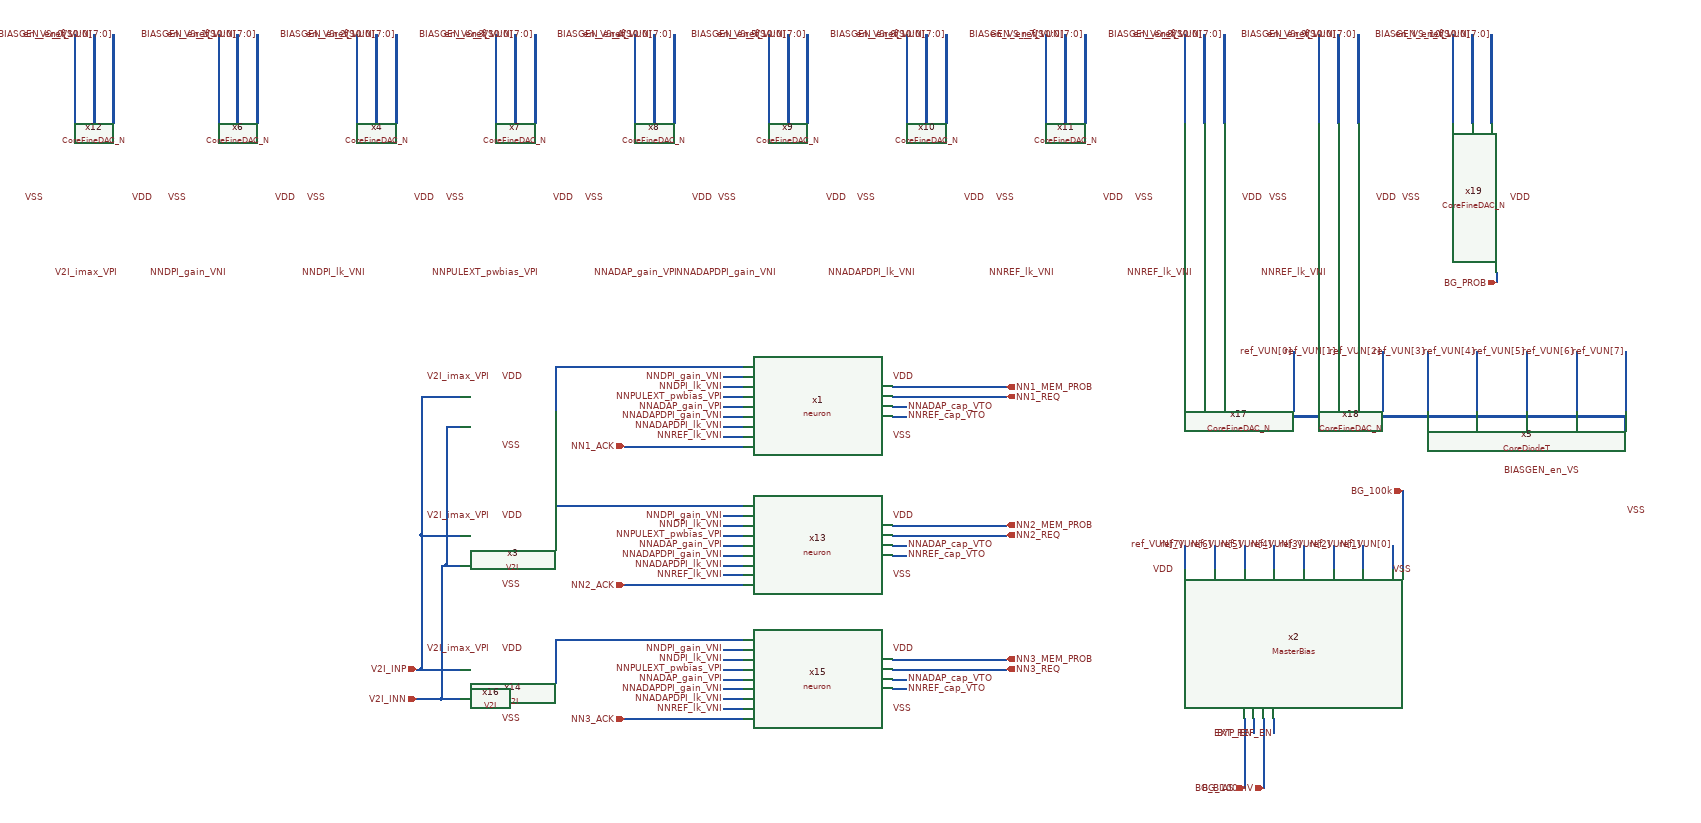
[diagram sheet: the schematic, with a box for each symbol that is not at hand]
v {xschem version=3.4.8RC file_version=1.3}
G {}
K {}
V {}
S {}
F {}
E {}
N 1110 210 1110 260 {lab=ref_VUN[0]}
N 1050 210 1050 260 {lab=ref_VUN[1]}
N 990 210 990 260 {lab=ref_VUN[2]}
N 930 210 930 260 {lab=ref_VUN[3]}
N 870 210 870 260 {lab=ref_VUN[4]}
N 810 210 810 260 {lab=ref_VUN[5]}
N 750 210 750 260 {lab=ref_VUN[6]}
N 690 210 690 260 {lab=ref_VUN[7]}
N 1580 -50 1580 -20 {lab=ref_VUN[7:0] bus=true}
N 910 -180 910 -60 {lab=ref_VUN[0]}
N 1000 -180 1000 -60 {lab=ref_VUN[1]}
N 1090 -180 1090 -60 {lab=ref_VUN[2]}
N 1180 -180 1180 -60 {lab=ref_VUN[3]}
N 1280 -180 1280 -60 {lab=ref_VUN[4]}
N 1380 -180 1380 -60 {lab=ref_VUN[5]}
N 1480 -180 1480 -60 {lab=ref_VUN[6]}
N 1580 -180 1580 -60 {lab=ref_VUN[7]}
N 900 -50 1580 -50 {lab=ref_VUN[7:0]  bus=true}
N -240 -90 -200 -90 {lab=NNPULEXT_pwbias_VPI}
N -240 -70 -200 -70 {lab=NNADAP_gain_VPI}
N -240 -50 -200 -50 {lab=NNADAPDPI_gain_VNI}
N -240 -30 -200 -30 {lab=NNADAPDPI_lk_VNI}
N -240 -10 -200 -10 {lab=NNREF_lk_VNI}
N -240 -110 -200 -110 {lab=NNDPI_lk_VNI}
N -240 -130 -200 -130 {lab=NNDPI_gain_VNI}
N 100 -110 330 -110 {lab=NN1_MEM_PROB}
N 100 -70 130 -70 {lab=NNADAP_cap_VTO}
N 100 -50 130 -50 {lab=NNREF_cap_VTO}
N -580 -150 -200 -150 {lab=#net1}
N -580 -150 -580 -60 {lab=#net1}
N -1220 -820 -1220 -640 {lab=en_VS_1[10:0] bus=true}
N -1260 -820 -1260 -640 {lab=BIASGEN_en_VS}
N -1180 -820 -1180 -640 {lab=ref_VUN[7:0] bus=true}
N -940 -820 -940 -640 {lab=en_VS_2[10:0] bus=true}
N -980 -820 -980 -640 {lab=BIASGEN_en_VS}
N -900 -820 -900 -640 {lab=ref_VUN[7:0] bus=true}
N -660 -820 -660 -640 {lab=en_VS_3[10:0] bus=true}
N -700 -820 -700 -640 {lab=BIASGEN_en_VS}
N -620 -820 -620 -640 {lab=ref_VUN[7:0] bus=true}
N -380 -820 -380 -640 {lab=en_VS_4[10:0] bus=true}
N -420 -820 -420 -640 {lab=BIASGEN_en_VS}
N -340 -820 -340 -640 {lab=ref_VUN[7:0] bus=true}
N -110 -820 -110 -640 {lab=en_VS_5[10:0] bus=true}
N -150 -820 -150 -640 {lab=BIASGEN_en_VS}
N -70 -820 -70 -640 {lab=ref_VUN[7:0] bus=true}
N 170 -820 170 -640 {lab=en_VS_6[10:0] bus=true}
N 130 -820 130 -640 {lab=BIASGEN_en_VS}
N 210 -820 210 -640 {lab=ref_VUN[7:0] bus=true}
N 450 -820 450 -640 {lab=en_VS__7[10:0] bus=true}
N 410 -820 410 -640 {lab=BIASGEN_en_VS}
N 490 -820 490 -640 {lab=ref_VUN[7:0] bus=true}
N -1510 -820 -1510 -640 {lab=en_VS_0[10:0] bus=true}
N -1550 -820 -1550 -640 {lab=BIASGEN_en_VS}
N -1470 -820 -1470 -640 {lab=ref_VUN[7:0] bus=true}
N -240 190 -200 190 {lab=NNPULEXT_pwbias_VPI}
N -240 210 -200 210 {lab=NNADAP_gain_VPI}
N -240 230 -200 230 {lab=NNADAPDPI_gain_VNI}
N -240 250 -200 250 {lab=NNADAPDPI_lk_VNI}
N -240 270 -200 270 {lab=NNREF_lk_VNI}
N -240 170 -200 170 {lab=NNDPI_lk_VNI}
N -240 150 -200 150 {lab=NNDPI_gain_VNI}
N 100 210 130 210 {lab=NNADAP_cap_VTO}
N 100 230 130 230 {lab=NNREF_cap_VTO}
N -580 130 -200 130 {lab=#net2}
N -580 130 -580 220 {lab=#net2}
N -240 460 -200 460 {lab=NNPULEXT_pwbias_VPI}
N -240 480 -200 480 {lab=NNADAP_gain_VPI}
N -240 500 -200 500 {lab=NNADAPDPI_gain_VNI}
N -240 520 -200 520 {lab=NNADAPDPI_lk_VNI}
N -240 540 -200 540 {lab=NNREF_lk_VNI}
N -240 440 -200 440 {lab=NNDPI_lk_VNI}
N -240 420 -200 420 {lab=NNDPI_gain_VNI}
N 100 440 330 440 {lab=NN3_MEM_PROB}
N 100 480 130 480 {lab=NNADAP_cap_VTO}
N 100 500 130 500 {lab=NNREF_cap_VTO}
N -580 400 -200 400 {lab=#net3}
N -580 400 -580 490 {lab=#net3}
N 100 -90 330 -90 {lab=NN1_REQ}
N 100 460 330 460 {lab=NN3_REQ}
N 100 190 330 190 {lab=NN2_REQ}
N -440 10 -200 10 {lab=NN1_ACK}
N -440 290 -200 290 {lab=NN2_ACK}
N -440 560 -200 560 {lab=NN3_ACK}
N 830 560 830 590 {lab=BYP_EN}
N 870 560 870 590 {lab=EXT_REF_EN}
N 850 560 850 700 {lab=BG_100mV}
N 810 560 810 700 {lab=BG_BIAS}
N 1130 100 1130 260 {lab=BG_100k}
N 730 -820 730 -640 {lab=en_VS_8[10:0] bus=true}
N 690 -820 690 -640 {lab=BIASGEN_en_VS}
N 770 -820 770 -640 {lab=ref_VUN[7:0] bus=true}
N 1000 -820 1000 -640 {lab=en_VS_9[10:0] bus=true}
N 960 -820 960 -640 {lab=BIASGEN_en_VS}
N 1040 -820 1040 -640 {lab=ref_VUN[7:0] bus=true}
N 1270 -820 1270 -640 {lab=en_VS_10[10:0] bus=true}
N 1230 -820 1230 -640 {lab=BIASGEN_en_VS}
N 1310 -820 1310 -640 {lab=ref_VUN[7:0] bus=true}
N 1320 -340 1320 -320 {lab=BG_PROB}
N 100 170 330 170 {lab=NN2_MEM_PROB}
N -850 460 -770 460 {lab=V2I_INP}
N -810 520 -770 520 {lab=V2I_INN}
N -850 190 -850 460 {lab=V2I_INP}
N -850 190 -770 190 {lab=V2I_INP}
N -860 460 -850 460 {lab=V2I_INP}
N -850 -90 -850 190 {lab=V2I_INP}
N -850 -90 -770 -90 {lab=V2I_INP}
N -810 250 -810 520 {lab=V2I_INN}
N -800 250 -770 250 {lab=V2I_INN}
N -860 520 -810 520 {lab=V2I_INN}
N -800 -30 -800 250 {lab=V2I_INN}
N -800 -30 -770 -30 {lab=V2I_INN}
N -810 250 -800 250 {lab=V2I_INN}
C {/foss/designs/ihp_INI_project/INI_Block/neuron.sym} -50 -60 0 0 {name=x1}
C {MasterBias.sym} 930 410 3 0 {name=x2}
C {lab_wire.sym} 1110 210 1 0 {name=p61 sig_type=std_logic lab=ref_VUN[0]
}
C {lab_wire.sym} 1050 210 1 0 {name=p62 sig_type=std_logic lab=ref_VUN[1]
}
C {lab_wire.sym} 990 210 1 0 {name=p63 sig_type=std_logic lab=ref_VUN[2]
}
C {lab_wire.sym} 930 210 1 0 {name=p64 sig_type=std_logic lab=ref_VUN[3]
}
C {lab_wire.sym} 870 210 1 0 {name=p65 sig_type=std_logic lab=ref_VUN[4]
}
C {lab_wire.sym} 750 210 1 0 {name=p66 sig_type=std_logic lab=ref_VUN[6]
}
C {lab_wire.sym} 810 210 1 0 {name=p67 sig_type=std_logic lab=ref_VUN[5]
}
C {lab_wire.sym} 690 210 1 0 {name=p68 sig_type=std_logic lab=ref_VUN[7]
}
C {lab_wire.sym} 1150 260 1 0 {name=p69 sig_type=std_logic lab=VSS
}
C {lab_wire.sym} 670 260 3 1 {name=p70 sig_type=std_logic lab=VDD
}
C {CoreDiodeT.sym} 1580 100 0 0 {name=x5}
C {lab_wire.sym} 1490 60 0 0 {name=p51 sig_type=std_logic lab=BIASGEN_en_VS
}
C {lab_wire.sym} 1580 140 2 0 {name=p52 sig_type=std_logic lab=VSS
}
C {lab_wire.sym} 910 -180 0 0 {name=p1 sig_type=std_logic lab=ref_VUN[0]
}
C {lab_wire.sym} 1000 -180 0 0 {name=p53 sig_type=std_logic lab=ref_VUN[1]
}
C {lab_wire.sym} 1090 -180 0 0 {name=p54 sig_type=std_logic lab=ref_VUN[2]
}
C {lab_wire.sym} 1180 -180 0 0 {name=p55 sig_type=std_logic lab=ref_VUN[3]
}
C {lab_wire.sym} 1280 -180 0 0 {name=p56 sig_type=std_logic lab=ref_VUN[4]
}
C {lab_wire.sym} 1480 -180 0 0 {name=p57 sig_type=std_logic lab=ref_VUN[6]
}
C {lab_wire.sym} 1380 -180 0 0 {name=p58 sig_type=std_logic lab=ref_VUN[5]
}
C {lab_wire.sym} 1580 -180 0 0 {name=p59 sig_type=std_logic lab=ref_VUN[7]
}
C {bus_connect_nolab.sym} 1270 -50 0 0 {name=r1}
C {bus_connect_nolab.sym} 1370 -50 0 0 {name=r2}
C {bus_connect_nolab.sym} 1470 -50 0 0 {name=r3}
C {bus_connect_nolab.sym} 1570 -50 0 0 {name=r4}
C {bus_connect_nolab.sym} 1170 -50 0 0 {name=r5}
C {bus_connect_nolab.sym} 1080 -50 0 0 {name=r6}
C {bus_connect_nolab.sym} 990 -50 0 0 {name=r7}
C {bus_connect_nolab.sym} 900 -50 0 0 {name=r8}
C {lab_wire.sym} 900 -50 0 0 {name=p60 sig_type=std_logic lab=ref_VUN[7:0]
}
C {lab_pin.sym} -240 -110 0 0 {name=p6 sig_type=std_logic lab=NNDPI_lk_VNI}
C {lab_pin.sym} -240 -70 0 0 {name=p8 sig_type=std_logic lab=NNADAP_gain_VPI}
C {lab_pin.sym} -240 -50 0 0 {name=p9 sig_type=std_logic lab=NNADAPDPI_gain_VNI}
C {lab_pin.sym} -240 -30 0 0 {name=p10 sig_type=std_logic lab=NNADAPDPI_lk_VNI}
C {lab_pin.sym} -240 -90 0 0 {name=p14 sig_type=std_logic lab=NNPULEXT_pwbias_VPI}
C {lab_pin.sym} -240 -130 0 0 {name=p32 sig_type=std_logic lab=NNDPI_gain_VNI}
C {lab_pin.sym} 130 -70 2 0 {name=p12 sig_type=std_logic lab=NNADAP_cap_VTO}
C {lab_pin.sym} 130 -50 2 0 {name=p15 sig_type=std_logic lab=NNREF_cap_VTO}
C {lab_pin.sym} -240 -10 0 0 {name=p24 sig_type=std_logic lab=NNREF_lk_VNI}
C {/foss/designs/ihp_INI_project/INI_Block/V2I.sym} -710 80 0 0 {name=x3}
C {lab_wire.sym} -690 10 2 0 {name=p11 sig_type=std_logic lab=VSS
}
C {lab_wire.sym} -690 -130 0 1 {name=p16 sig_type=std_logic lab=VDD
}
C {lab_wire.sym} 100 -10 2 0 {name=p17 sig_type=std_logic lab=VSS
}
C {lab_wire.sym} 100 -130 0 1 {name=p18 sig_type=std_logic lab=VDD
}
C {/foss/designs/ihp_INI_project/INI_Block/CoreFineDAC_N.sym} -1160 -490 1 0 {name=x6}
C {lab_wire.sym} -1220 -820 1 0 {name=p20 sig_type=std_logic lab=en_VS_1[10:0]
}
C {lab_wire.sym} -1260 -820 1 0 {name=p21 sig_type=std_logic lab=BIASGEN_en_VS
}
C {lab_wire.sym} -1320 -490 3 0 {name=p22 sig_type=std_logic lab=VSS
}
C {lab_wire.sym} -1100 -490 1 1 {name=p23 sig_type=std_logic lab=VDD
}
C {lab_wire.sym} -1180 -820 1 0 {name=p25 sig_type=std_logic lab=ref_VUN[7:0]
}
C {lab_pin.sym} -1240 -340 1 1 {name=p26 sig_type=std_logic lab=NNDPI_gain_VNI}
C {/foss/designs/ihp_INI_project/INI_Block/CoreFineDAC_N.sym} -880 -490 1 0 {name=x4}
C {lab_wire.sym} -940 -820 1 0 {name=p2 sig_type=std_logic lab=en_VS_2[10:0]
}
C {lab_wire.sym} -980 -820 1 0 {name=p3 sig_type=std_logic lab=BIASGEN_en_VS
}
C {lab_wire.sym} -1040 -490 3 0 {name=p4 sig_type=std_logic lab=VSS
}
C {lab_wire.sym} -820 -490 1 1 {name=p5 sig_type=std_logic lab=VDD
}
C {lab_wire.sym} -900 -820 1 0 {name=p7 sig_type=std_logic lab=ref_VUN[7:0]
}
C {lab_pin.sym} -960 -340 3 0 {name=p27 sig_type=std_logic lab=NNDPI_lk_VNI}
C {/foss/designs/ihp_INI_project/INI_Block/CoreFineDAC_N.sym} -600 -490 1 0 {name=x7}
C {lab_wire.sym} -660 -820 1 0 {name=p19 sig_type=std_logic lab=en_VS_3[10:0]
}
C {lab_wire.sym} -700 -820 1 0 {name=p28 sig_type=std_logic lab=BIASGEN_en_VS
}
C {lab_wire.sym} -760 -490 3 0 {name=p29 sig_type=std_logic lab=VSS
}
C {lab_wire.sym} -540 -490 1 1 {name=p30 sig_type=std_logic lab=VDD
}
C {lab_wire.sym} -620 -820 1 0 {name=p31 sig_type=std_logic lab=ref_VUN[7:0]
}
C {/foss/designs/ihp_INI_project/INI_Block/CoreFineDAC_N.sym} -320 -490 1 0 {name=x8}
C {lab_wire.sym} -380 -820 1 0 {name=p34 sig_type=std_logic lab=en_VS_4[10:0]
}
C {lab_wire.sym} -420 -820 1 0 {name=p35 sig_type=std_logic lab=BIASGEN_en_VS
}
C {lab_wire.sym} -480 -490 3 0 {name=p36 sig_type=std_logic lab=VSS
}
C {lab_wire.sym} -260 -490 1 1 {name=p37 sig_type=std_logic lab=VDD
}
C {lab_wire.sym} -340 -820 1 0 {name=p38 sig_type=std_logic lab=ref_VUN[7:0]
}
C {lab_pin.sym} -610 -340 3 0 {name=p39 sig_type=std_logic lab=NNPULEXT_pwbias_VPI}
C {lab_pin.sym} -330 -340 3 0 {name=p40 sig_type=std_logic lab=NNADAP_gain_VPI}
C {/foss/designs/ihp_INI_project/INI_Block/CoreFineDAC_N.sym} -50 -490 1 0 {name=x9}
C {lab_wire.sym} -110 -820 1 0 {name=p33 sig_type=std_logic lab=en_VS_5[10:0]
}
C {lab_wire.sym} -150 -820 1 0 {name=p41 sig_type=std_logic lab=BIASGEN_en_VS
}
C {lab_wire.sym} -210 -490 3 0 {name=p42 sig_type=std_logic lab=VSS
}
C {lab_wire.sym} 10 -490 1 1 {name=p43 sig_type=std_logic lab=VDD
}
C {lab_wire.sym} -70 -820 1 0 {name=p44 sig_type=std_logic lab=ref_VUN[7:0]
}
C {/foss/designs/ihp_INI_project/INI_Block/CoreFineDAC_N.sym} 230 -490 1 0 {name=x10}
C {lab_wire.sym} 170 -820 1 0 {name=p46 sig_type=std_logic lab=en_VS_6[10:0]
}
C {lab_wire.sym} 130 -820 1 0 {name=p47 sig_type=std_logic lab=BIASGEN_en_VS
}
C {lab_wire.sym} 70 -490 3 0 {name=p48 sig_type=std_logic lab=VSS
}
C {lab_wire.sym} 290 -490 1 1 {name=p49 sig_type=std_logic lab=VDD
}
C {lab_wire.sym} 210 -820 1 0 {name=p50 sig_type=std_logic lab=ref_VUN[7:0]
}
C {/foss/designs/ihp_INI_project/INI_Block/CoreFineDAC_N.sym} 510 -490 1 0 {name=x11}
C {lab_wire.sym} 450 -820 1 0 {name=p72 sig_type=std_logic lab=en_VS__7[10:0]
}
C {lab_wire.sym} 410 -820 1 0 {name=p73 sig_type=std_logic lab=BIASGEN_en_VS
}
C {lab_wire.sym} 350 -490 3 0 {name=p74 sig_type=std_logic lab=VSS
}
C {lab_wire.sym} 570 -490 1 1 {name=p75 sig_type=std_logic lab=VDD
}
C {lab_wire.sym} 490 -820 1 0 {name=p76 sig_type=std_logic lab=ref_VUN[7:0]
}
C {/foss/designs/ihp_INI_project/INI_Block/CoreFineDAC_N.sym} -1450 -490 1 0 {name=x12}
C {lab_wire.sym} -1510 -820 1 0 {name=p77 sig_type=std_logic lab=en_VS_0[10:0]
}
C {lab_wire.sym} -1550 -820 1 0 {name=p78 sig_type=std_logic lab=BIASGEN_en_VS
}
C {lab_wire.sym} -1610 -490 3 0 {name=p79 sig_type=std_logic lab=VSS
}
C {lab_wire.sym} -1390 -490 1 1 {name=p80 sig_type=std_logic lab=VDD
}
C {lab_wire.sym} -1470 -820 1 0 {name=p81 sig_type=std_logic lab=ref_VUN[7:0]
}
C {lab_pin.sym} -1460 -340 3 0 {name=p83 sig_type=std_logic lab=V2I_imax_VPI}
C {lab_pin.sym} -710 -130 1 0 {name=p84 sig_type=std_logic lab=V2I_imax_VPI}
C {lab_pin.sym} -130 -340 3 0 {name=p45 sig_type=std_logic lab=NNADAPDPI_gain_VNI}
C {lab_pin.sym} 150 -340 3 0 {name=p71 sig_type=std_logic lab=NNADAPDPI_lk_VNI}
C {lab_pin.sym} 430 -340 3 0 {name=p82 sig_type=std_logic lab=NNREF_lk_VNI}
C {/foss/designs/ihp_INI_project/INI_Block/neuron.sym} -50 220 0 0 {name=x13}
C {lab_pin.sym} -240 170 0 0 {name=p85 sig_type=std_logic lab=NNDPI_lk_VNI}
C {lab_pin.sym} -240 210 0 0 {name=p86 sig_type=std_logic lab=NNADAP_gain_VPI}
C {lab_pin.sym} -240 230 0 0 {name=p87 sig_type=std_logic lab=NNADAPDPI_gain_VNI}
C {lab_pin.sym} -240 250 0 0 {name=p88 sig_type=std_logic lab=NNADAPDPI_lk_VNI}
C {lab_pin.sym} -240 190 0 0 {name=p89 sig_type=std_logic lab=NNPULEXT_pwbias_VPI}
C {lab_pin.sym} -240 150 0 0 {name=p90 sig_type=std_logic lab=NNDPI_gain_VNI}
C {lab_pin.sym} 130 210 2 0 {name=p91 sig_type=std_logic lab=NNADAP_cap_VTO}
C {lab_pin.sym} 130 230 2 0 {name=p93 sig_type=std_logic lab=NNREF_cap_VTO}
C {lab_pin.sym} -240 270 0 0 {name=p94 sig_type=std_logic lab=NNREF_lk_VNI}
C {/foss/designs/ihp_INI_project/INI_Block/V2I.sym} -710 360 0 0 {name=x14}
C {lab_wire.sym} -690 290 2 0 {name=p95 sig_type=std_logic lab=VSS
}
C {lab_wire.sym} -690 150 0 1 {name=p96 sig_type=std_logic lab=VDD
}
C {lab_wire.sym} 100 270 2 0 {name=p97 sig_type=std_logic lab=VSS
}
C {lab_wire.sym} 100 150 0 1 {name=p98 sig_type=std_logic lab=VDD
}
C {lab_pin.sym} -710 150 1 0 {name=p99 sig_type=std_logic lab=V2I_imax_VPI}
C {/foss/designs/ihp_INI_project/INI_Block/neuron.sym} -50 490 0 0 {name=x15}
C {lab_pin.sym} -240 440 0 0 {name=p100 sig_type=std_logic lab=NNDPI_lk_VNI}
C {lab_pin.sym} -240 480 0 0 {name=p101 sig_type=std_logic lab=NNADAP_gain_VPI}
C {lab_pin.sym} -240 500 0 0 {name=p102 sig_type=std_logic lab=NNADAPDPI_gain_VNI}
C {lab_pin.sym} -240 520 0 0 {name=p103 sig_type=std_logic lab=NNADAPDPI_lk_VNI}
C {lab_pin.sym} -240 460 0 0 {name=p104 sig_type=std_logic lab=NNPULEXT_pwbias_VPI}
C {lab_pin.sym} -240 420 0 0 {name=p105 sig_type=std_logic lab=NNDPI_gain_VNI}
C {lab_pin.sym} 130 480 2 0 {name=p106 sig_type=std_logic lab=NNADAP_cap_VTO}
C {lab_pin.sym} 130 500 2 0 {name=p108 sig_type=std_logic lab=NNREF_cap_VTO}
C {lab_pin.sym} -240 540 0 0 {name=p109 sig_type=std_logic lab=NNREF_lk_VNI}
C {/foss/designs/ihp_INI_project/INI_Block/V2I.sym} -710 630 0 0 {name=x16}
C {lab_wire.sym} -690 560 2 0 {name=p110 sig_type=std_logic lab=VSS
}
C {lab_wire.sym} -690 420 0 1 {name=p111 sig_type=std_logic lab=VDD
}
C {lab_wire.sym} 100 540 2 0 {name=p112 sig_type=std_logic lab=VSS
}
C {lab_wire.sym} 100 420 0 1 {name=p113 sig_type=std_logic lab=VDD
}
C {lab_pin.sym} -710 420 1 0 {name=p114 sig_type=std_logic lab=V2I_imax_VPI}
C {opin.sym} 330 -90 0 0 {name=p115 lab=NN1_REQ}
C {opin.sym} 330 190 0 0 {name=p116 lab=NN2_REQ}
C {opin.sym} 330 460 0 0 {name=p117 lab=NN3_REQ}
C {ipin.sym} -440 10 0 0 {name=p118 lab=NN1_ACK}
C {ipin.sym} -440 290 0 0 {name=p119 lab=NN2_ACK}
C {ipin.sym} -440 560 0 0 {name=p120 lab=NN3_ACK}
C {lab_wire.sym} 870 590 3 0 {name=p121 sig_type=std_logic lab=EXT_REF_EN
}
C {lab_wire.sym} 830 590 3 0 {name=p122 sig_type=std_logic lab=BYP_EN
}
C {iopin.sym} 850 700 1 0 {name=p123 lab=BG_100mV}
C {ipin.sym} 810 700 3 0 {name=p124 lab=BG_BIAS}
C {iopin.sym} 1130 100 3 0 {name=p125 lab=BG_100k}
C {/foss/designs/ihp_INI_project/INI_Block/CoreFineDAC_N.sym} 790 -490 1 0 {name=x17}
C {lab_wire.sym} 730 -820 1 0 {name=p126 sig_type=std_logic lab=en_VS_8[10:0]
}
C {lab_wire.sym} 690 -820 1 0 {name=p127 sig_type=std_logic lab=BIASGEN_en_VS
}
C {lab_wire.sym} 630 -490 3 0 {name=p128 sig_type=std_logic lab=VSS
}
C {lab_wire.sym} 850 -490 1 1 {name=p129 sig_type=std_logic lab=VDD
}
C {lab_wire.sym} 770 -820 1 0 {name=p130 sig_type=std_logic lab=ref_VUN[7:0]
}
C {lab_pin.sym} 710 -340 3 0 {name=p131 sig_type=std_logic lab=NNREF_lk_VNI}
C {/foss/designs/ihp_INI_project/INI_Block/CoreFineDAC_N.sym} 1060 -490 1 0 {name=x18}
C {lab_wire.sym} 1000 -820 1 0 {name=p132 sig_type=std_logic lab=en_VS_9[10:0]
}
C {lab_wire.sym} 960 -820 1 0 {name=p133 sig_type=std_logic lab=BIASGEN_en_VS
}
C {lab_wire.sym} 900 -490 3 0 {name=p134 sig_type=std_logic lab=VSS
}
C {lab_wire.sym} 1120 -490 1 1 {name=p135 sig_type=std_logic lab=VDD
}
C {lab_wire.sym} 1040 -820 1 0 {name=p136 sig_type=std_logic lab=ref_VUN[7:0]
}
C {lab_pin.sym} 980 -340 3 0 {name=p137 sig_type=std_logic lab=NNREF_lk_VNI}
C {/foss/designs/ihp_INI_project/INI_Block/CoreFineDAC_N.sym} 1330 -490 1 0 {name=x19}
C {lab_wire.sym} 1270 -820 1 0 {name=p138 sig_type=std_logic lab=en_VS_10[10:0]
}
C {lab_wire.sym} 1230 -820 1 0 {name=p139 sig_type=std_logic lab=BIASGEN_en_VS
}
C {lab_wire.sym} 1170 -490 3 0 {name=p140 sig_type=std_logic lab=VSS
}
C {lab_wire.sym} 1390 -490 1 1 {name=p141 sig_type=std_logic lab=VDD
}
C {lab_wire.sym} 1310 -820 1 0 {name=p142 sig_type=std_logic lab=ref_VUN[7:0]
}
C {iopin.sym} 1320 -320 1 0 {name=p144 lab=BG_PROB}
C {opin.sym} 330 170 0 0 {name=p92 lab=NN2_MEM_PROB}
C {opin.sym} 330 -110 0 0 {name=p143 lab=NN1_MEM_PROB}
C {opin.sym} 330 440 0 0 {name=p13 lab=NN3_MEM_PROB}
C {ipin.sym} -860 520 0 0 {name=p107 lab=V2I_INN}
C {ipin.sym} -860 460 0 0 {name=p145 lab=V2I_INP}
